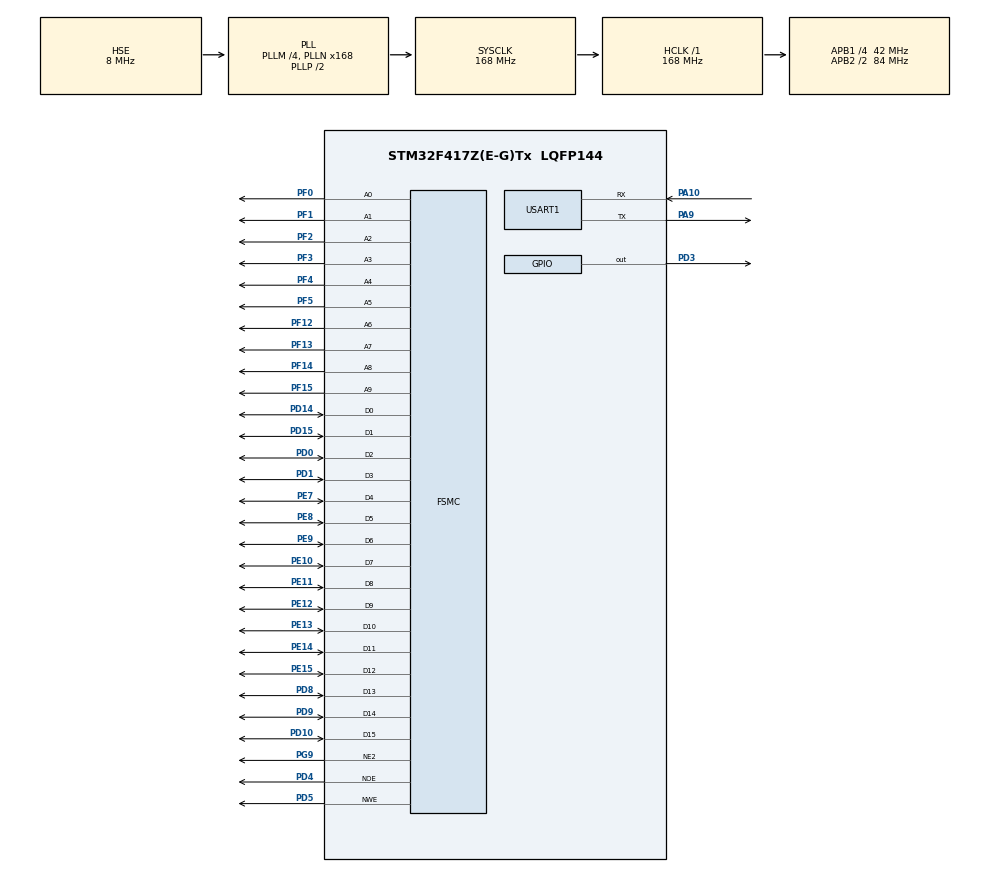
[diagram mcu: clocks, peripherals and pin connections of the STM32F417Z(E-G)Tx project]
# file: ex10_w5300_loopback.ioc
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Mcu.Family=STM32F4
FSMC.AddressSetupTime1=5
PH0-OSC_IN.Signal=RCC_OSC_IN
RCC.CortexFreq_Value=168000000
SH.FSMC_D1_DA1.0=FSMC_D1,16b-d1
SH.FSMC_A6.0=FSMC_A6,10b-a1
SH.FSMC_NWE.0=FSMC_NWE,Sram1
SH.FSMC_D0_DA0.0=FSMC_D0,16b-d1
RCC.SYSCLKSource=RCC_SYSCLKSOURCE_PLLCLK
ProjectManager.StackSize=0x400
SH.FSMC_A7.0=FSMC_A7,10b-a1
RCC.HCLKFreq_Value=168000000
PD4.Signal=FSMC_NOE
RCC.APB2TimFreq_Value=168000000
PF12.Signal=FSMC_A6
PD0.Signal=FSMC_D2_DA2
PD8.Signal=FSMC_D13_DA13
RCC.AHBFreq_Value=168000000
PH0-OSC_IN.Mode=HSE-External-Oscillator
RCC.HSE_VALUE=8000000
PE13.Signal=FSMC_D10_DA10
SH.FSMC_D14_DA14.0=FSMC_D14,16b-d1
SH.FSMC_D10_DA10.0=FSMC_D10,16b-d1
PE9.Signal=FSMC_D6_DA6
PA14.Mode=Serial_Wire
SH.FSMC_A0.0=FSMC_A0,10b-a1
SH.FSMC_D6_DA6.0=FSMC_D6,16b-d1
SH.FSMC_A8.0=FSMC_A8,10b-a1
FSMC.BusTurnAroundDuration1=5
PF3.Signal=FSMC_A3
PE10.Signal=FSMC_D7_DA7
SH.FSMC_D5_DA5.0=FSMC_D5,16b-d1
SH.FSMC_D4_DA4.0=FSMC_D4,16b-d1
PH1-OSC_OUT.Mode=HSE-External-Oscillator
Mcu.Package=LQFP144
SH.FSMC_D13_DA13.0=FSMC_D13,16b-d1
PA10.Signal=USART1_RX
PF5.Signal=FSMC_A5
SH.FSMC_A1.0=FSMC_A1,10b-a1
RCC.APB2CLKDivider=RCC_HCLK_DIV2
SH.FSMC_D3_DA3.0=FSMC_D3,16b-d1
SH.FSMC_A9.0=FSMC_A9,10b-a1
PF14.Signal=FSMC_A8
RCC.APB1TimFreq_Value=84000000
SH.FSMC_D2_DA2.0=FSMC_D2,16b-d1
PF0.Signal=FSMC_A0
PE7.Signal=FSMC_D4_DA4
PD15.Signal=FSMC_D1_DA1
RCC.PLLSourceVirtual=RCC_PLLSOURCE_HSE
SH.FSMC_D12_DA12.0=FSMC_D12,16b-d1
SH.FSMC_A2.0=FSMC_A2,10b-a1
PA10.Mode=Asynchronous
FSMC.WriteOperation1=FSMC_WRITE_OPERATION_ENABLE
PG9.Signal=FSMC_NE2
PD3.Signal=GPIO_Output
PG9.Mode=NorPsramChipSelect2_1
PD1.Signal=FSMC_D3_DA3
SH.FSMC_D9_DA9.0=FSMC_D9,16b-d1
PD9.Signal=FSMC_D14_DA14
PD5.Signal=FSMC_NWE
RCC.APB1CLKDivider=RCC_HCLK_DIV4
SH.FSMC_D8_DA8.0=FSMC_D8,16b-d1
PD10.Signal=FSMC_D15_DA15
PA13.Signal=SYS_JTMS-SWDIO
PA9.Mode=Asynchronous
SH.FSMC_A3.0=FSMC_A3,10b-a1
ProjectManager.TargetToolchain=STM32CubeIDE
FSMC.DataSetupTime1=5
PA9.Signal=USART1_TX
PF2.Signal=FSMC_A2
PE11.Signal=FSMC_D8_DA8
RCC.LSE_VALUE=32768
SH.FSMC_D7_DA7.0=FSMC_D7,16b-d1
board=custom
RCC.VCOOutputFreq_Value=336000000
RCC.APB2Freq_Value=84000000
PE14.Signal=FSMC_D11_DA11
PE15.Signal=FSMC_D12_DA12
PE8.Signal=FSMC_D5_DA5
SH.FSMC_A4.0=FSMC_A4,10b-a1
PH1-OSC_OUT.Signal=RCC_OSC_OUT
PF15.Signal=FSMC_A9
PF13.Signal=FSMC_A7
PF1.Signal=FSMC_A1
PA13.Mode=Serial_Wire
Mcu.Name=STM32F417Z(E-G)Tx
PE12.Signal=FSMC_D9_DA9
PD14.Signal=FSMC_D0_DA0
RCC.48MHZClocksFreq_Value=84000000
RCC.SYSCLKFreq_VALUE=168000000
USART1.VirtualMode=VM_ASYNC
SH.FSMC_D15_DA15.0=FSMC_D15,16b-d1
PA14.Signal=SYS_JTCK-SWCLK
ProjectManager.HeapSize=0x200
SH.FSMC_D11_DA11.0=FSMC_D11,16b-d1
SH.FSMC_NOE.0=FSMC_NOE,Sram1
RCC.HSI_VALUE=16000000
NVIC.PriorityGroup=NVIC_PRIORITYGROUP_4
SH.FSMC_A5.0=FSMC_A5,10b-a1
RCC.PLLM=4
RCC.PLLN=168
PF4.Signal=FSMC_A4
RCC.APB1Freq_Value=42000000

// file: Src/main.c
/* USER CODE BEGIN Header */
/**
  ******************************************************************************
  * @file           : main.c
  * @brief          : Main program body
  ******************************************************************************
  * @attention
  *
  * <h2><center>&copy; Copyright (c) 2021 STMicroelectronics.
  * All rights reserved.</center></h2>
  *
  * This software component is licensed by ST under BSD 3-Clause license,
  * the "License"; You may not use this file except in compliance with the
  * License. You may obtain a copy of the License at:
  *                        opensource.org/licenses/BSD-3-Clause
  *
  *
  * by https://github.com/elabsystem/STM32_RP
  ******************************************************************************
  */
/* USER CODE END Header */
#include "main.h"

UART_HandleTypeDef huart1;

SRAM_HandleTypeDef hsram1;

void SystemClock_Config(void);
static void MX_GPIO_Init(void);
static void MX_FSMC_Init(void);
static void MX_USART1_UART_Init(void);

/* USER CODE BEGIN 0 */
#include "_user_code_intit.h"
#include "_user_code_w5300.h"
/* USER CODE END 0 */

int main(void)
{

  /* MCU Configuration--------------------------------------------------------*/

  /* Reset of all peripherals, Initializes the Flash interface and the Systick. */
  HAL_Init();

  /* Configure the system clock */
  SystemClock_Config();

  /* Initialize all configured peripherals */
  MX_GPIO_Init();
  MX_FSMC_Init();
  MX_USART1_UART_Init();
  /* USER CODE BEGIN 2 */
  //printf("W5300 Hello World!\r\n");
  printf("W5300 TCP Loopback Test\r\n");

  _InitW5300();
  /* USER CODE END 2 */

  /* Infinite loop */
  while (1)
  {
	  loopback_tcps(0, ethBuf0, 3000);
  }
}

void SystemClock_Config(void)
{
  RCC_OscInitTypeDef RCC_OscInitStruct = {0};
  RCC_ClkInitTypeDef RCC_ClkInitStruct = {0};

  /** Configure the main internal regulator output voltage
  */
  __HAL_RCC_PWR_CLK_ENABLE();
  __HAL_PWR_VOLTAGESCALING_CONFIG(PWR_REGULATOR_VOLTAGE_SCALE1);
  /** Initializes the RCC Oscillators according to the specified parameters
  * in the RCC_OscInitTypeDef structure.
  */
  RCC_OscInitStruct.OscillatorType = RCC_OSCILLATORTYPE_HSE;
  RCC_OscInitStruct.HSEState = RCC_HSE_ON;
  RCC_OscInitStruct.PLL.PLLState = RCC_PLL_ON;
  RCC_OscInitStruct.PLL.PLLSource = RCC_PLLSOURCE_HSE;
  RCC_OscInitStruct.PLL.PLLM = 4;
  RCC_OscInitStruct.PLL.PLLN = 168;
  RCC_OscInitStruct.PLL.PLLP = RCC_PLLP_DIV2;
  RCC_OscInitStruct.PLL.PLLQ = 4;
  if (HAL_RCC_OscConfig(&RCC_OscInitStruct) != HAL_OK)
  {
    Error_Handler();
  }
  /** Initializes the CPU, AHB and APB buses clocks
  */
  RCC_ClkInitStruct.ClockType = RCC_CLOCKTYPE_HCLK|RCC_CLOCKTYPE_SYSCLK
                              |RCC_CLOCKTYPE_PCLK1|RCC_CLOCKTYPE_PCLK2;
  RCC_ClkInitStruct.SYSCLKSource = RCC_SYSCLKSOURCE_PLLCLK;
  RCC_ClkInitStruct.AHBCLKDivider = RCC_SYSCLK_DIV1;
  RCC_ClkInitStruct.APB1CLKDivider = RCC_HCLK_DIV4;
  RCC_ClkInitStruct.APB2CLKDivider = RCC_HCLK_DIV2;

  if (HAL_RCC_ClockConfig(&RCC_ClkInitStruct, FLASH_LATENCY_5) != HAL_OK)
  {
    Error_Handler();
  }
}

static void MX_USART1_UART_Init(void)
{

  huart1.Instance = USART1;
  huart1.Init.BaudRate = 115200;
  huart1.Init.WordLength = UART_WORDLENGTH_8B;
  huart1.Init.StopBits = UART_STOPBITS_1;
  huart1.Init.Parity = UART_PARITY_NONE;
  huart1.Init.Mode = UART_MODE_TX_RX;
  huart1.Init.HwFlowCtl = UART_HWCONTROL_NONE;
  huart1.Init.OverSampling = UART_OVERSAMPLING_16;
  if (HAL_UART_Init(&huart1) != HAL_OK)
  {
    Error_Handler();
  }

}

static void MX_GPIO_Init(void)
{
  GPIO_InitTypeDef GPIO_InitStruct = {0};

  /* GPIO Ports Clock Enable */
  __HAL_RCC_GPIOF_CLK_ENABLE();
  __HAL_RCC_GPIOH_CLK_ENABLE();
  __HAL_RCC_GPIOE_CLK_ENABLE();
  __HAL_RCC_GPIOD_CLK_ENABLE();
  __HAL_RCC_GPIOA_CLK_ENABLE();
  __HAL_RCC_GPIOG_CLK_ENABLE();

  /*Configure GPIO pin Output Level */
  HAL_GPIO_WritePin(GPIOD, GPIO_PIN_3, GPIO_PIN_RESET);

  /*Configure GPIO pin : PD3 */
  GPIO_InitStruct.Pin = GPIO_PIN_3;
  GPIO_InitStruct.Mode = GPIO_MODE_OUTPUT_PP;
  GPIO_InitStruct.Pull = GPIO_NOPULL;
  GPIO_InitStruct.Speed = GPIO_SPEED_FREQ_LOW;
  HAL_GPIO_Init(GPIOD, &GPIO_InitStruct);

  GPIO_InitStruct.Pin = GPIO_PIN_1;
  GPIO_InitStruct.Mode = GPIO_MODE_OUTPUT_PP;
  GPIO_InitStruct.Pull = GPIO_NOPULL;
  GPIO_InitStruct.Speed = GPIO_SPEED_FREQ_LOW;
  HAL_GPIO_Init(GPIOB, &GPIO_InitStruct);

  GPIO_InitStruct.Pin = GPIO_PIN_2;
  GPIO_InitStruct.Mode = GPIO_MODE_OUTPUT_PP;
  GPIO_InitStruct.Pull = GPIO_NOPULL;
  GPIO_InitStruct.Speed = GPIO_SPEED_FREQ_LOW;
  HAL_GPIO_Init(GPIOC, &GPIO_InitStruct);

}

/* FSMC initialization function */
static void MX_FSMC_Init(void)
{

  FSMC_NORSRAM_TimingTypeDef Timing = {0};

  /** Perform the SRAM1 memory initialization sequence
  */
  hsram1.Instance = FSMC_NORSRAM_DEVICE;
  hsram1.Extended = FSMC_NORSRAM_EXTENDED_DEVICE;
  /* hsram1.Init */
  hsram1.Init.NSBank = FSMC_NORSRAM_BANK2;
  hsram1.Init.DataAddressMux = FSMC_DATA_ADDRESS_MUX_DISABLE;
  hsram1.Init.MemoryType = FSMC_MEMORY_TYPE_SRAM;
  hsram1.Init.MemoryDataWidth = FSMC_NORSRAM_MEM_BUS_WIDTH_16;
  hsram1.Init.BurstAccessMode = FSMC_BURST_ACCESS_MODE_DISABLE;
  hsram1.Init.WaitSignalPolarity = FSMC_WAIT_SIGNAL_POLARITY_LOW;
  hsram1.Init.WrapMode = FSMC_WRAP_MODE_DISABLE;
  hsram1.Init.WaitSignalActive = FSMC_WAIT_TIMING_BEFORE_WS;
  hsram1.Init.WriteOperation = FSMC_WRITE_OPERATION_ENABLE;
  hsram1.Init.WaitSignal = FSMC_WAIT_SIGNAL_DISABLE;
  hsram1.Init.ExtendedMode = FSMC_EXTENDED_MODE_DISABLE;
  hsram1.Init.AsynchronousWait = FSMC_ASYNCHRONOUS_WAIT_DISABLE;
  hsram1.Init.WriteBurst = FSMC_WRITE_BURST_DISABLE;
  hsram1.Init.PageSize = FSMC_PAGE_SIZE_NONE;
  /* Timing */
  /*
  Timing.AddressSetupTime = 4;
  Timing.AddressHoldTime = 4;
  Timing.DataSetupTime = 4;
  Timing.BusTurnAroundDuration = 4;
  Timing.CLKDivision = 6;
  Timing.DataLatency = 6;
  */

  Timing.AddressSetupTime = 3;
  Timing.AddressHoldTime = 3;
  Timing.DataSetupTime = 4;
  Timing.BusTurnAroundDuration = 4;
  Timing.CLKDivision = 10;
  Timing.DataLatency = 10;
  Timing.AccessMode = FSMC_ACCESS_MODE_A;
  /* ExtTiming */

  if (HAL_SRAM_Init(&hsram1, &Timing, NULL) != HAL_OK)
  {
    Error_Handler( );
  }

}

void Error_Handler(void)
{
  __disable_irq();
  while (1)
  {
  }
}

/************************ (C) COPYRIGHT STMicroelectronics *****END OF FILE****/
